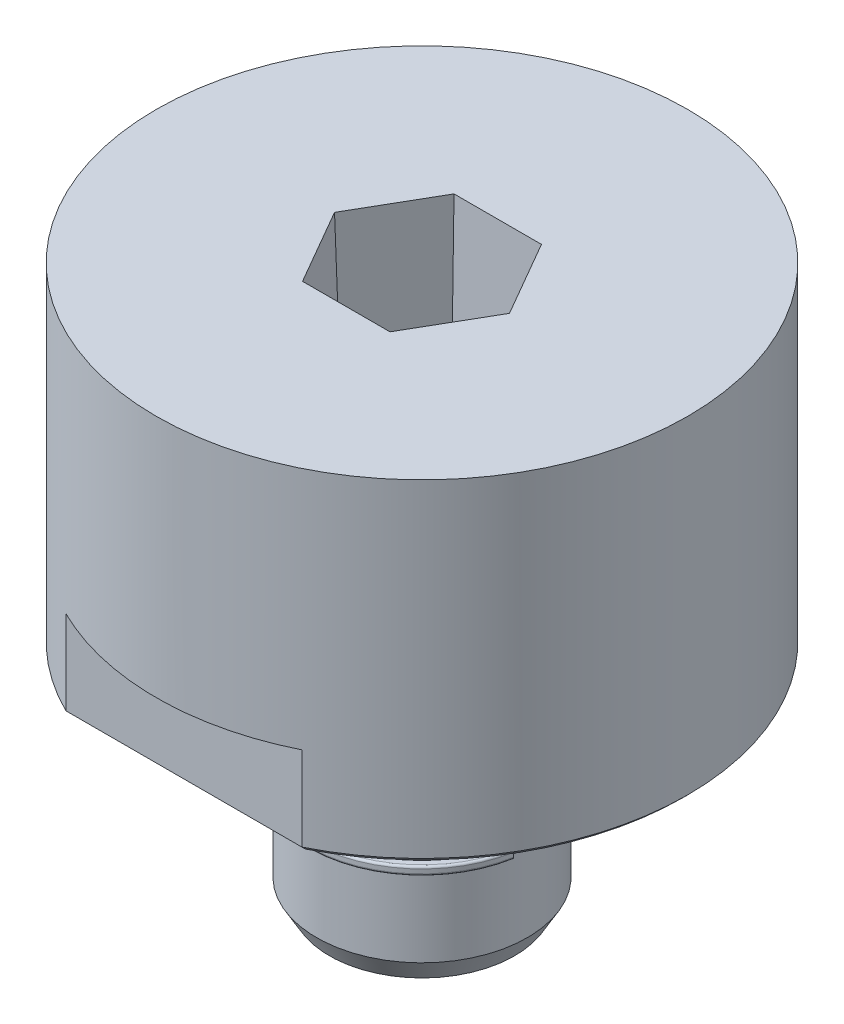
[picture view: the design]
ISO-10303-21;
HEADER;
FILE_DESCRIPTION(('STEP AP214'),'2;1');
FILE_NAME('part.step','',(''),(''),'','','');
FILE_SCHEMA(('AUTOMOTIVE_DESIGN { 1 0 10303 214 1 1 1 1 }'));
ENDSEC;
DATA;
#1=APPLICATION_CONTEXT('core data for automotive mechanical design processes');
#2=APPLICATION_PROTOCOL_DEFINITION('international standard','automotive_design',2000,#1);
#3=PRODUCT_CONTEXT('',#1,'mechanical');
#4=PRODUCT('Part','Part','',(#3));
#5=PRODUCT_RELATED_PRODUCT_CATEGORY('part','',(#4));
#6=PRODUCT_DEFINITION_FORMATION('','',#4);
#7=PRODUCT_DEFINITION_CONTEXT('part definition',#1,'design');
#8=PRODUCT_DEFINITION('design','',#6,#7);
#9=PRODUCT_DEFINITION_SHAPE('','',#8);
#10=(LENGTH_UNIT() NAMED_UNIT(*) SI_UNIT(.MILLI.,.METRE.));
#11=(NAMED_UNIT(*) PLANE_ANGLE_UNIT() SI_UNIT($,.RADIAN.));
#12=(NAMED_UNIT(*) SI_UNIT($,.STERADIAN.) SOLID_ANGLE_UNIT());
#13=UNCERTAINTY_MEASURE_WITH_UNIT(LENGTH_MEASURE(1.E-05),#10,'distance_accuracy_value','');
#14=(GEOMETRIC_REPRESENTATION_CONTEXT(3) GLOBAL_UNCERTAINTY_ASSIGNED_CONTEXT((#13)) GLOBAL_UNIT_ASSIGNED_CONTEXT((#10,
#11,#12)) REPRESENTATION_CONTEXT('',''));
#15=CARTESIAN_POINT('',(0.,0.,0.));
#16=DIRECTION('',(0.,0.,1.));
#17=DIRECTION('',(1.,0.,0.));
#18=AXIS2_PLACEMENT_3D('',#15,#16,#17);
#19=CARTESIAN_POINT('',(0.,3.5395,0.));
#20=DIRECTION('',(0.,-1.,0.));
#21=DIRECTION('',(1.,0.,0.));
#22=AXIS2_PLACEMENT_3D('',#19,#20,#21);
#23=CYLINDRICAL_SURFACE('',#22,4.4577);
#24=CARTESIAN_POINT('',(0.,4.71425,0.));
#25=DIRECTION('',(0.,-1.,0.));
#26=DIRECTION('',(0.,0.,-1.));
#27=AXIS2_PLACEMENT_3D('',#24,#25,#26);
#28=CIRCLE('',#27,4.4577);
#29=CARTESIAN_POINT('',(4.38997752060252,4.71425,0.774071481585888));
#30=VERTEX_POINT('',#29);
#31=CARTESIAN_POINT('',(4.38997752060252,4.71425,-0.774071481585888));
#32=VERTEX_POINT('',#31);
#33=EDGE_CURVE('E12',#30,#32,#28,.T.);
#34=ORIENTED_EDGE('',*,*,#33,.T.);
#35=DIRECTION('',(0.,1.,0.));
#36=VECTOR('',#35,1.);
#37=CARTESIAN_POINT('',(4.38997752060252,3.5395,-0.774071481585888));
#38=LINE('',#37,#36);
#39=CARTESIAN_POINT('',(4.38997752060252,4.90475,-0.774071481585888));
#40=VERTEX_POINT('',#39);
#41=EDGE_CURVE('E62',#32,#40,#38,.T.);
#42=ORIENTED_EDGE('',*,*,#41,.T.);
#43=CARTESIAN_POINT('',(0.,4.90475,0.));
#44=DIRECTION('',(0.,-1.,0.));
#45=DIRECTION('',(0.,0.,-1.));
#46=AXIS2_PLACEMENT_3D('',#43,#44,#45);
#47=CIRCLE('',#46,4.4577);
#48=CARTESIAN_POINT('',(4.38997752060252,4.90475,0.774071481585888));
#49=VERTEX_POINT('',#48);
#50=EDGE_CURVE('E137',#49,#40,#47,.T.);
#51=ORIENTED_EDGE('',*,*,#50,.F.);
#52=DIRECTION('',(0.,-1.,0.));
#53=VECTOR('',#52,1.);
#54=CARTESIAN_POINT('',(4.38997752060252,3.5395,0.774071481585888));
#55=LINE('',#54,#53);
#56=EDGE_CURVE('E202',#49,#30,#55,.T.);
#57=ORIENTED_EDGE('',*,*,#56,.T.);
#58=EDGE_LOOP('',(#34,#42,#51,#57));
#59=FACE_BOUND('',#58,.T.);
#60=ADVANCED_FACE('F54',(#59),#23,.F.);
#61=CARTESIAN_POINT('',(0.,5.1905,0.));
#62=DIRECTION('',(0.173648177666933,0.,-0.984807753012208));
#63=DIRECTION('',(-0.984807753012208,0.,-0.173648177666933));
#64=AXIS2_PLACEMENT_3D('',#61,#62,#63);
#65=PLANE('',#64);
#66=CARTESIAN_POINT('',(4.48378045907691,4.90475000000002,0.79061147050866));
#67=DIRECTION('',(-0.173648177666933,0.,0.984807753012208));
#68=DIRECTION('',(-0.984807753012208,0.,-0.173648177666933));
#69=AXIS2_PLACEMENT_3D('',#66,#67,#68);
#70=CIRCLE('',#69,0.09524999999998);
#71=CARTESIAN_POINT('',(4.48378045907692,5.,0.790611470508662));
#72=VERTEX_POINT('',#71);
#73=EDGE_CURVE('E198',#72,#49,#70,.T.);
#74=ORIENTED_EDGE('',*,*,#73,.F.);
#75=DIRECTION('',(-0.984807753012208,0.,-0.173648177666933));
#76=VECTOR('',#75,1.);
#77=CARTESIAN_POINT('',(4.84675844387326,5.,0.854614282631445));
#78=LINE('',#77,#76);
#79=CARTESIAN_POINT('',(4.92152750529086,5.,0.867798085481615));
#80=VERTEX_POINT('',#79);
#81=EDGE_CURVE('E131',#80,#72,#78,.T.);
#82=ORIENTED_EDGE('',*,*,#81,.F.);
#83=CARTESIAN_POINT('',(4.92152750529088,4.90475000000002,0.867798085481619));
#84=DIRECTION('',(-0.173648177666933,0.,0.984807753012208));
#85=DIRECTION('',(-0.984807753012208,0.,-0.173648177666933));
#86=AXIS2_PLACEMENT_3D('',#83,#84,#85);
#87=CIRCLE('',#86,0.0952499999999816);
#88=CARTESIAN_POINT('',(5.01533044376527,4.90475,0.884338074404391));
#89=VERTEX_POINT('',#88);
#90=EDGE_CURVE('E190',#89,#80,#87,.T.);
#91=ORIENTED_EDGE('',*,*,#90,.F.);
#92=DIRECTION('',(0.,1.,0.));
#93=VECTOR('',#92,1.);
#94=CARTESIAN_POINT('',(5.01533044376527,3.5395,0.884338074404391));
#95=LINE('',#94,#93);
#96=CARTESIAN_POINT('',(5.01533044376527,4.71425,0.884338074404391));
#97=VERTEX_POINT('',#96);
#98=EDGE_CURVE('E185',#97,#89,#95,.T.);
#99=ORIENTED_EDGE('',*,*,#98,.F.);
#100=CARTESIAN_POINT('',(4.92152750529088,4.71424999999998,0.867798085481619));
#101=DIRECTION('',(-0.173648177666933,0.,0.984807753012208));
#102=DIRECTION('',(-0.984807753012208,0.,-0.173648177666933));
#103=AXIS2_PLACEMENT_3D('',#100,#101,#102);
#104=CIRCLE('',#103,0.0952499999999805);
#105=CARTESIAN_POINT('',(4.92152750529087,4.619,0.867798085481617));
#106=VERTEX_POINT('',#105);
#107=EDGE_CURVE('E180',#106,#97,#104,.T.);
#108=ORIENTED_EDGE('',*,*,#107,.F.);
#109=DIRECTION('',(0.984807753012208,0.,0.173648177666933));
#110=VECTOR('',#109,1.);
#111=CARTESIAN_POINT('',(4.4156617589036,4.619,0.778600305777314));
#112=LINE('',#111,#110);
#113=CARTESIAN_POINT('',(4.48378045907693,4.619,0.790611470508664));
#114=VERTEX_POINT('',#113);
#115=EDGE_CURVE('E175',#114,#106,#112,.T.);
#116=ORIENTED_EDGE('',*,*,#115,.F.);
#117=CARTESIAN_POINT('',(4.48378045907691,4.71424999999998,0.79061147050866));
#118=DIRECTION('',(-0.173648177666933,0.,0.984807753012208));
#119=DIRECTION('',(-0.984807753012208,0.,-0.173648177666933));
#120=AXIS2_PLACEMENT_3D('',#117,#118,#119);
#121=CIRCLE('',#120,0.0952499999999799);
#122=EDGE_CURVE('E170',#30,#114,#121,.T.);
#123=ORIENTED_EDGE('',*,*,#122,.F.);
#124=ORIENTED_EDGE('',*,*,#56,.F.);
#125=EDGE_LOOP('',(#74,#82,#91,#99,#108,#116,#123,#124));
#126=FACE_BOUND('',#125,.T.);
#127=ADVANCED_FACE('F216',(#126),#65,.T.);
#128=CARTESIAN_POINT('',(0.,4.71424999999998,0.));
#129=DIRECTION('',(0.,-1.,0.));
#130=DIRECTION('',(1.,0.,0.));
#131=AXIS2_PLACEMENT_3D('',#128,#129,#130);
#132=TOROIDAL_SURFACE('',#131,4.55295,0.0952499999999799);
#133=CARTESIAN_POINT('',(0.,4.619,0.));
#134=DIRECTION('',(0.,-1.,0.));
#135=DIRECTION('',(0.,0.,-1.));
#136=AXIS2_PLACEMENT_3D('',#133,#134,#135);
#137=CIRCLE('',#136,4.55295);
#138=CARTESIAN_POINT('',(4.48378045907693,4.619,-0.790611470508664));
#139=VERTEX_POINT('',#138);
#140=EDGE_CURVE('E166',#114,#139,#137,.T.);
#141=ORIENTED_EDGE('',*,*,#140,.T.);
#142=CARTESIAN_POINT('',(4.48378045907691,4.71424999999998,-0.79061147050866));
#143=DIRECTION('',(-0.173648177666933,0.,-0.984807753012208));
#144=DIRECTION('',(0.984807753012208,0.,-0.173648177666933));
#145=AXIS2_PLACEMENT_3D('',#142,#143,#144);
#146=CIRCLE('',#145,0.0952499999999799);
#147=EDGE_CURVE('E162',#139,#32,#146,.T.);
#148=ORIENTED_EDGE('',*,*,#147,.T.);
#149=ORIENTED_EDGE('',*,*,#33,.F.);
#150=ORIENTED_EDGE('',*,*,#122,.T.);
#151=EDGE_LOOP('',(#141,#148,#149,#150));
#152=FACE_BOUND('',#151,.T.);
#153=ADVANCED_FACE('F219',(#152),#132,.T.);
#154=CARTESIAN_POINT('',(5.17291938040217,5.1905,-0.912125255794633));
#155=DIRECTION('',(0.173648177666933,0.,0.984807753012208));
#156=DIRECTION('',(0.984807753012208,0.,-0.173648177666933));
#157=AXIS2_PLACEMENT_3D('',#154,#155,#156);
#158=PLANE('',#157);
#159=ORIENTED_EDGE('',*,*,#147,.F.);
#160=DIRECTION('',(-0.984807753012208,0.,0.173648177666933));
#161=VECTOR('',#160,1.);
#162=CARTESIAN_POINT('',(4.4156617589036,4.619,-0.778600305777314));
#163=LINE('',#162,#161);
#164=CARTESIAN_POINT('',(4.92152750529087,4.619,-0.867798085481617));
#165=VERTEX_POINT('',#164);
#166=EDGE_CURVE('E157',#165,#139,#163,.T.);
#167=ORIENTED_EDGE('',*,*,#166,.F.);
#168=CARTESIAN_POINT('',(4.92152750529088,4.71424999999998,-0.867798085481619));
#169=DIRECTION('',(-0.173648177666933,0.,-0.984807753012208));
#170=DIRECTION('',(0.984807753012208,0.,-0.173648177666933));
#171=AXIS2_PLACEMENT_3D('',#168,#169,#170);
#172=CIRCLE('',#171,0.0952499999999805);
#173=CARTESIAN_POINT('',(5.01533044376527,4.71425,-0.884338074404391));
#174=VERTEX_POINT('',#173);
#175=EDGE_CURVE('E152',#174,#165,#172,.T.);
#176=ORIENTED_EDGE('',*,*,#175,.F.);
#177=DIRECTION('',(0.,-1.,0.));
#178=VECTOR('',#177,1.);
#179=CARTESIAN_POINT('',(5.01533044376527,3.5395,-0.884338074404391));
#180=LINE('',#179,#178);
#181=CARTESIAN_POINT('',(5.01533044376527,4.90475,-0.884338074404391));
#182=VERTEX_POINT('',#181);
#183=EDGE_CURVE('E147',#182,#174,#180,.T.);
#184=ORIENTED_EDGE('',*,*,#183,.F.);
#185=CARTESIAN_POINT('',(4.92152750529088,4.90475000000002,-0.867798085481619));
#186=DIRECTION('',(-0.173648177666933,0.,-0.984807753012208));
#187=DIRECTION('',(0.984807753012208,0.,-0.173648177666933));
#188=AXIS2_PLACEMENT_3D('',#185,#186,#187);
#189=CIRCLE('',#188,0.0952499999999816);
#190=CARTESIAN_POINT('',(4.92152750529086,5.,-0.867798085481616));
#191=VERTEX_POINT('',#190);
#192=EDGE_CURVE('E122',#191,#182,#189,.T.);
#193=ORIENTED_EDGE('',*,*,#192,.F.);
#194=DIRECTION('',(0.984807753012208,0.,-0.173648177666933));
#195=VECTOR('',#194,1.);
#196=CARTESIAN_POINT('',(4.84675844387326,5.,-0.854614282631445));
#197=LINE('',#196,#195);
#198=CARTESIAN_POINT('',(4.48378045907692,5.,-0.790611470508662));
#199=VERTEX_POINT('',#198);
#200=EDGE_CURVE('E114',#199,#191,#197,.T.);
#201=ORIENTED_EDGE('',*,*,#200,.F.);
#202=CARTESIAN_POINT('',(4.48378045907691,4.90475000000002,-0.79061147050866));
#203=DIRECTION('',(-0.173648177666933,0.,-0.984807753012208));
#204=DIRECTION('',(0.984807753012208,0.,-0.173648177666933));
#205=AXIS2_PLACEMENT_3D('',#202,#203,#204);
#206=CIRCLE('',#205,0.09524999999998);
#207=EDGE_CURVE('E119',#40,#199,#206,.T.);
#208=ORIENTED_EDGE('',*,*,#207,.F.);
#209=ORIENTED_EDGE('',*,*,#41,.F.);
#210=EDGE_LOOP('',(#159,#167,#176,#184,#193,#201,#208,#209));
#211=FACE_BOUND('',#210,.T.);
#212=ADVANCED_FACE('F117',(#211),#158,.T.);
#213=CARTESIAN_POINT('',(0.,4.90475000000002,0.));
#214=DIRECTION('',(0.,-1.,0.));
#215=DIRECTION('',(1.,0.,0.));
#216=AXIS2_PLACEMENT_3D('',#213,#214,#215);
#217=TOROIDAL_SURFACE('',#216,4.55295,0.09524999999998);
#218=ORIENTED_EDGE('',*,*,#50,.T.);
#219=ORIENTED_EDGE('',*,*,#207,.T.);
#220=CARTESIAN_POINT('',(0.,5.,0.));
#221=DIRECTION('',(0.,-1.,0.));
#222=DIRECTION('',(0.,0.,-1.));
#223=AXIS2_PLACEMENT_3D('',#220,#221,#222);
#224=CIRCLE('',#223,4.55295);
#225=EDGE_CURVE('E129',#72,#199,#224,.T.);
#226=ORIENTED_EDGE('',*,*,#225,.F.);
#227=ORIENTED_EDGE('',*,*,#73,.T.);
#228=EDGE_LOOP('',(#218,#219,#226,#227));
#229=FACE_BOUND('',#228,.T.);
#230=ADVANCED_FACE('F136',(#229),#217,.T.);
#231=CARTESIAN_POINT('',(4.99745,5.,0.));
#232=DIRECTION('',(0.,1.,0.));
#233=DIRECTION('',(0.,0.,1.));
#234=AXIS2_PLACEMENT_3D('',#231,#232,#233);
#235=PLANE('',#234);
#236=ORIENTED_EDGE('',*,*,#225,.T.);
#237=ORIENTED_EDGE('',*,*,#200,.T.);
#238=CARTESIAN_POINT('',(0.,5.,0.));
#239=DIRECTION('',(0.,-1.,0.));
#240=DIRECTION('',(0.,0.,-1.));
#241=AXIS2_PLACEMENT_3D('',#238,#239,#240);
#242=CIRCLE('',#241,4.99745);
#243=EDGE_CURVE('E134',#80,#191,#242,.T.);
#244=ORIENTED_EDGE('',*,*,#243,.F.);
#245=ORIENTED_EDGE('',*,*,#81,.T.);
#246=EDGE_LOOP('',(#236,#237,#244,#245));
#247=FACE_BOUND('',#246,.T.);
#248=ADVANCED_FACE('F130',(#247),#235,.T.);
#249=CARTESIAN_POINT('',(0.,4.90475000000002,0.));
#250=DIRECTION('',(0.,-1.,0.));
#251=DIRECTION('',(1.,0.,0.));
#252=AXIS2_PLACEMENT_3D('',#249,#250,#251);
#253=TOROIDAL_SURFACE('',#252,4.99745,0.0952499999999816);
#254=ORIENTED_EDGE('',*,*,#243,.T.);
#255=ORIENTED_EDGE('',*,*,#192,.T.);
#256=CARTESIAN_POINT('',(0.,4.90475,0.));
#257=DIRECTION('',(0.,-1.,0.));
#258=DIRECTION('',(0.,0.,-1.));
#259=AXIS2_PLACEMENT_3D('',#256,#257,#258);
#260=CIRCLE('',#259,5.0927);
#261=EDGE_CURVE('E232',#89,#182,#260,.T.);
#262=ORIENTED_EDGE('',*,*,#261,.F.);
#263=ORIENTED_EDGE('',*,*,#90,.T.);
#264=EDGE_LOOP('',(#254,#255,#262,#263));
#265=FACE_BOUND('',#264,.T.);
#266=ADVANCED_FACE('F246',(#265),#253,.T.);
#267=CARTESIAN_POINT('',(0.,3.5395,0.));
#268=DIRECTION('',(0.,-1.,0.));
#269=DIRECTION('',(1.,0.,0.));
#270=AXIS2_PLACEMENT_3D('',#267,#268,#269);
#271=CYLINDRICAL_SURFACE('',#270,5.0927);
#272=ORIENTED_EDGE('',*,*,#261,.T.);
#273=ORIENTED_EDGE('',*,*,#183,.T.);
#274=CARTESIAN_POINT('',(0.,4.71425,0.));
#275=DIRECTION('',(0.,-1.,0.));
#276=DIRECTION('',(0.,0.,-1.));
#277=AXIS2_PLACEMENT_3D('',#274,#275,#276);
#278=CIRCLE('',#277,5.0927);
#279=EDGE_CURVE('E226',#97,#174,#278,.T.);
#280=ORIENTED_EDGE('',*,*,#279,.F.);
#281=ORIENTED_EDGE('',*,*,#98,.T.);
#282=EDGE_LOOP('',(#272,#273,#280,#281));
#283=FACE_BOUND('',#282,.T.);
#284=ADVANCED_FACE('F248',(#283),#271,.T.);
#285=CARTESIAN_POINT('',(0.,4.71424999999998,0.));
#286=DIRECTION('',(0.,-1.,0.));
#287=DIRECTION('',(1.,0.,0.));
#288=AXIS2_PLACEMENT_3D('',#285,#286,#287);
#289=TOROIDAL_SURFACE('',#288,4.99745,0.0952499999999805);
#290=ORIENTED_EDGE('',*,*,#279,.T.);
#291=ORIENTED_EDGE('',*,*,#175,.T.);
#292=CARTESIAN_POINT('',(0.,4.619,0.));
#293=DIRECTION('',(0.,-1.,0.));
#294=DIRECTION('',(0.,0.,-1.));
#295=AXIS2_PLACEMENT_3D('',#292,#293,#294);
#296=CIRCLE('',#295,4.99745);
#297=EDGE_CURVE('E223',#106,#165,#296,.T.);
#298=ORIENTED_EDGE('',*,*,#297,.F.);
#299=ORIENTED_EDGE('',*,*,#107,.T.);
#300=EDGE_LOOP('',(#290,#291,#298,#299));
#301=FACE_BOUND('',#300,.T.);
#302=ADVANCED_FACE('F229',(#301),#289,.T.);
#303=CARTESIAN_POINT('',(4.55295,4.619,0.));
#304=DIRECTION('',(0.,-1.,0.));
#305=DIRECTION('',(0.,0.,-1.));
#306=AXIS2_PLACEMENT_3D('',#303,#304,#305);
#307=PLANE('',#306);
#308=ORIENTED_EDGE('',*,*,#297,.T.);
#309=ORIENTED_EDGE('',*,*,#166,.T.);
#310=ORIENTED_EDGE('',*,*,#140,.F.);
#311=ORIENTED_EDGE('',*,*,#115,.T.);
#312=EDGE_LOOP('',(#308,#309,#310,#311));
#313=FACE_BOUND('',#312,.T.);
#314=ADVANCED_FACE('F224',(#313),#307,.T.);
#315=CLOSED_SHELL('',(#60,#127,#153,#212,#230,#248,#266,#284,#302,#314));
#316=MANIFOLD_SOLID_BREP('B2',#315);
#317=CARTESIAN_POINT('',(4.18264973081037,0.,0.));
#318=DIRECTION('',(0.,-1.,0.));
#319=DIRECTION('',(0.,0.,-1.));
#320=AXIS2_PLACEMENT_3D('',#317,#318,#319);
#321=PLANE('',#320);
#322=CARTESIAN_POINT('',(0.,0.,0.));
#323=DIRECTION('',(0.,-1.,0.));
#324=DIRECTION('',(0.,0.,-1.));
#325=AXIS2_PLACEMENT_3D('',#322,#323,#324);
#326=CIRCLE('',#325,3.00000000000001);
#327=CARTESIAN_POINT('',(0.,0.,-3.00000000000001));
#328=VERTEX_POINT('',#327);
#329=EDGE_CURVE('E360',#328,#328,#326,.F.);
#330=ORIENTED_EDGE('',*,*,#329,.T.);
#331=EDGE_LOOP('',(#330));
#332=FACE_BOUND('',#331,.T.);
#333=CARTESIAN_POINT('',(0.,0.,0.));
#334=DIRECTION('',(0.,-1.,0.));
#335=DIRECTION('',(0.,0.,-1.));
#336=AXIS2_PLACEMENT_3D('',#333,#334,#335);
#337=CIRCLE('',#336,4.18264973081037);
#338=CARTESIAN_POINT('',(0.,0.,-4.18264973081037));
#339=VERTEX_POINT('',#338);
#340=EDGE_CURVE('E554',#339,#339,#337,.T.);
#341=ORIENTED_EDGE('',*,*,#340,.T.);
#342=EDGE_LOOP('',(#341));
#343=FACE_BOUND('',#342,.T.);
#344=ADVANCED_FACE('F350',(#332,#343),#321,.T.);
#345=CARTESIAN_POINT('',(0.,25.,0.));
#346=DIRECTION('',(0.,1.,0.));
#347=DIRECTION('',(0.,0.,1.));
#348=AXIS2_PLACEMENT_3D('',#345,#346,#347);
#349=PLANE('',#348);
#350=DIRECTION('',(0.5,0.,0.866025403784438));
#351=VECTOR('',#350,1.);
#352=CARTESIAN_POINT('',(2.96098349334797,25.,-1.70952461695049));
#353=LINE('',#352,#351);
#354=CARTESIAN_POINT('',(3.94797799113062,25.,0.));
#355=VERTEX_POINT('',#354);
#356=CARTESIAN_POINT('',(1.97398899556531,25.,-3.41904923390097));
#357=VERTEX_POINT('',#356);
#358=EDGE_CURVE('E517',#355,#357,#353,.F.);
#359=ORIENTED_EDGE('',*,*,#358,.F.);
#360=DIRECTION('',(-0.5,0.,0.866025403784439));
#361=VECTOR('',#360,1.);
#362=CARTESIAN_POINT('',(2.96098349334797,25.,1.70952461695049));
#363=LINE('',#362,#361);
#364=CARTESIAN_POINT('',(1.97398899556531,25.,3.41904923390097));
#365=VERTEX_POINT('',#364);
#366=EDGE_CURVE('E427',#365,#355,#363,.F.);
#367=ORIENTED_EDGE('',*,*,#366,.F.);
#368=DIRECTION('',(-1.,0.,0.));
#369=VECTOR('',#368,1.);
#370=CARTESIAN_POINT('',(0.,25.,3.41904923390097));
#371=LINE('',#370,#369);
#372=CARTESIAN_POINT('',(-1.97398899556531,25.,3.41904923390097));
#373=VERTEX_POINT('',#372);
#374=EDGE_CURVE('E405',#373,#365,#371,.F.);
#375=ORIENTED_EDGE('',*,*,#374,.F.);
#376=DIRECTION('',(-0.5,0.,-0.866025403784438));
#377=VECTOR('',#376,1.);
#378=CARTESIAN_POINT('',(-2.96098349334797,25.,1.70952461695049));
#379=LINE('',#378,#377);
#380=CARTESIAN_POINT('',(-3.94797799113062,25.,0.));
#381=VERTEX_POINT('',#380);
#382=EDGE_CURVE('E416',#381,#373,#379,.F.);
#383=ORIENTED_EDGE('',*,*,#382,.F.);
#384=DIRECTION('',(0.5,0.,-0.866025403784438));
#385=VECTOR('',#384,1.);
#386=CARTESIAN_POINT('',(-2.96098349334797,25.,-1.70952461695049));
#387=LINE('',#386,#385);
#388=CARTESIAN_POINT('',(-1.97398899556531,25.,-3.41904923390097));
#389=VERTEX_POINT('',#388);
#390=EDGE_CURVE('E422',#389,#381,#387,.F.);
#391=ORIENTED_EDGE('',*,*,#390,.F.);
#392=DIRECTION('',(1.,0.,0.));
#393=VECTOR('',#392,1.);
#394=CARTESIAN_POINT('',(0.,25.,-3.41904923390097));
#395=LINE('',#394,#393);
#396=EDGE_CURVE('E515',#357,#389,#395,.F.);
#397=ORIENTED_EDGE('',*,*,#396,.F.);
#398=EDGE_LOOP('',(#359,#367,#375,#383,#391,#397));
#399=FACE_BOUND('',#398,.T.);
#400=CARTESIAN_POINT('',(0.,25.,0.));
#401=DIRECTION('',(0.,-1.,0.));
#402=DIRECTION('',(0.,0.,-1.));
#403=AXIS2_PLACEMENT_3D('',#400,#401,#402);
#404=CIRCLE('',#403,11.9975);
#405=CARTESIAN_POINT('',(0.,25.,-11.9975));
#406=VERTEX_POINT('',#405);
#407=EDGE_CURVE('E588',#406,#406,#404,.T.);
#408=ORIENTED_EDGE('',*,*,#407,.F.);
#409=EDGE_LOOP('',(#408));
#410=FACE_BOUND('',#409,.T.);
#411=ADVANCED_FACE('F425',(#399,#410),#349,.T.);
#412=CARTESIAN_POINT('',(0.,0.,0.));
#413=DIRECTION('',(0.,-1.,0.));
#414=DIRECTION('',(0.,0.,-1.));
#415=AXIS2_PLACEMENT_3D('',#412,#413,#414);
#416=CYLINDRICAL_SURFACE('',#415,11.9975);
#417=DIRECTION('',(0.,-1.,0.));
#418=VECTOR('',#417,1.);
#419=CARTESIAN_POINT('',(5.32705418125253,14.,10.75));
#420=LINE('',#419,#418);
#421=CARTESIAN_POINT('',(5.32705418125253,14.,10.75));
#422=VERTEX_POINT('',#421);
#423=CARTESIAN_POINT('',(5.32705418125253,10.2,10.75));
#424=VERTEX_POINT('',#423);
#425=EDGE_CURVE('E552',#422,#424,#420,.T.);
#426=ORIENTED_EDGE('',*,*,#425,.T.);
#427=CARTESIAN_POINT('',(0.,10.2,0.));
#428=DIRECTION('',(0.,-1.,0.));
#429=DIRECTION('',(0.,0.,-1.));
#430=AXIS2_PLACEMENT_3D('',#427,#428,#429);
#431=CIRCLE('',#430,11.9975);
#432=CARTESIAN_POINT('',(5.32705418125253,10.2,-10.75));
#433=VERTEX_POINT('',#432);
#434=EDGE_CURVE('E436',#424,#433,#431,.F.);
#435=ORIENTED_EDGE('',*,*,#434,.T.);
#436=DIRECTION('',(0.,-1.,0.));
#437=VECTOR('',#436,1.);
#438=CARTESIAN_POINT('',(5.32705418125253,14.,-10.75));
#439=LINE('',#438,#437);
#440=CARTESIAN_POINT('',(5.32705418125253,14.,-10.75));
#441=VERTEX_POINT('',#440);
#442=EDGE_CURVE('E556',#441,#433,#439,.T.);
#443=ORIENTED_EDGE('',*,*,#442,.F.);
#444=CARTESIAN_POINT('',(0.,14.,0.));
#445=DIRECTION('',(0.,-1.,0.));
#446=DIRECTION('',(0.,0.,-1.));
#447=AXIS2_PLACEMENT_3D('',#444,#445,#446);
#448=CIRCLE('',#447,11.9975);
#449=CARTESIAN_POINT('',(-5.32705418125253,14.,-10.75));
#450=VERTEX_POINT('',#449);
#451=EDGE_CURVE('E548',#450,#441,#448,.T.);
#452=ORIENTED_EDGE('',*,*,#451,.F.);
#453=DIRECTION('',(0.,-1.,0.));
#454=VECTOR('',#453,1.);
#455=CARTESIAN_POINT('',(-5.32705418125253,14.,-10.75));
#456=LINE('',#455,#454);
#457=CARTESIAN_POINT('',(-5.32705418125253,10.2,-10.75));
#458=VERTEX_POINT('',#457);
#459=EDGE_CURVE('E508',#450,#458,#456,.T.);
#460=ORIENTED_EDGE('',*,*,#459,.T.);
#461=CARTESIAN_POINT('',(0.,10.2,0.));
#462=DIRECTION('',(0.,-1.,0.));
#463=DIRECTION('',(0.,0.,-1.));
#464=AXIS2_PLACEMENT_3D('',#461,#462,#463);
#465=CIRCLE('',#464,11.9975);
#466=CARTESIAN_POINT('',(-5.32705418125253,10.2,10.75));
#467=VERTEX_POINT('',#466);
#468=EDGE_CURVE('E368',#458,#467,#465,.F.);
#469=ORIENTED_EDGE('',*,*,#468,.T.);
#470=DIRECTION('',(0.,-1.,0.));
#471=VECTOR('',#470,1.);
#472=CARTESIAN_POINT('',(-5.32705418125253,14.,10.75));
#473=LINE('',#472,#471);
#474=CARTESIAN_POINT('',(-5.32705418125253,14.,10.75));
#475=VERTEX_POINT('',#474);
#476=EDGE_CURVE('E551',#475,#467,#473,.T.);
#477=ORIENTED_EDGE('',*,*,#476,.F.);
#478=CARTESIAN_POINT('',(0.,14.,0.));
#479=DIRECTION('',(0.,-1.,0.));
#480=DIRECTION('',(0.,0.,-1.));
#481=AXIS2_PLACEMENT_3D('',#478,#479,#480);
#482=CIRCLE('',#481,11.9975);
#483=EDGE_CURVE('E544',#422,#475,#482,.T.);
#484=ORIENTED_EDGE('',*,*,#483,.F.);
#485=EDGE_LOOP('',(#426,#435,#443,#452,#460,#469,#477,#484));
#486=FACE_BOUND('',#485,.T.);
#487=ORIENTED_EDGE('',*,*,#407,.T.);
#488=EDGE_LOOP('',(#487));
#489=FACE_BOUND('',#488,.T.);
#490=ADVANCED_FACE('F632',(#486,#489),#416,.T.);
#491=CARTESIAN_POINT('',(11.9975,10.,0.));
#492=DIRECTION('',(0.,-1.,0.));
#493=DIRECTION('',(0.,0.,-1.));
#494=AXIS2_PLACEMENT_3D('',#491,#492,#493);
#495=PLANE('',#494);
#496=CARTESIAN_POINT('',(0.,10.,0.));
#497=DIRECTION('',(0.,-1.,0.));
#498=DIRECTION('',(0.,0.,-1.));
#499=AXIS2_PLACEMENT_3D('',#496,#497,#498);
#500=CIRCLE('',#499,11.7975);
#501=CARTESIAN_POINT('',(-5.28001006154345,10.,10.55));
#502=VERTEX_POINT('',#501);
#503=CARTESIAN_POINT('',(-5.28001006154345,10.,-10.55));
#504=VERTEX_POINT('',#503);
#505=EDGE_CURVE('E594',#502,#504,#500,.T.);
#506=ORIENTED_EDGE('',*,*,#505,.T.);
#507=DIRECTION('',(1.,0.,0.));
#508=VECTOR('',#507,1.);
#509=CARTESIAN_POINT('',(5.32705418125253,10.,-10.55));
#510=LINE('',#509,#508);
#511=CARTESIAN_POINT('',(5.28001006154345,10.,-10.55));
#512=VERTEX_POINT('',#511);
#513=EDGE_CURVE('E603',#504,#512,#510,.T.);
#514=ORIENTED_EDGE('',*,*,#513,.T.);
#515=CARTESIAN_POINT('',(0.,10.,0.));
#516=DIRECTION('',(0.,-1.,0.));
#517=DIRECTION('',(0.,0.,-1.));
#518=AXIS2_PLACEMENT_3D('',#515,#516,#517);
#519=CIRCLE('',#518,11.7975);
#520=CARTESIAN_POINT('',(5.28001006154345,10.,10.55));
#521=VERTEX_POINT('',#520);
#522=EDGE_CURVE('E600',#512,#521,#519,.T.);
#523=ORIENTED_EDGE('',*,*,#522,.T.);
#524=DIRECTION('',(-1.,0.,0.));
#525=VECTOR('',#524,1.);
#526=CARTESIAN_POINT('',(-5.32705418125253,10.,10.55));
#527=LINE('',#526,#525);
#528=EDGE_CURVE('E597',#521,#502,#527,.T.);
#529=ORIENTED_EDGE('',*,*,#528,.T.);
#530=EDGE_LOOP('',(#506,#514,#523,#529));
#531=FACE_BOUND('',#530,.T.);
#532=CARTESIAN_POINT('',(6.50538238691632,10.,-6.50538238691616));
#533=DIRECTION('',(0.,-1.,0.));
#534=DIRECTION('',(-0.707106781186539,0.,-0.707106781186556));
#535=AXIS2_PLACEMENT_3D('',#532,#533,#534);
#536=CIRCLE('',#535,0.916515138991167);
#537=CARTESIAN_POINT('',(5.85730831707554,10.,-7.15345645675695));
#538=VERTEX_POINT('',#537);
#539=EDGE_CURVE('E496',#538,#538,#536,.T.);
#540=ORIENTED_EDGE('',*,*,#539,.F.);
#541=EDGE_LOOP('',(#540));
#542=FACE_BOUND('',#541,.T.);
#543=CARTESIAN_POINT('',(0.,10.,-9.2));
#544=DIRECTION('',(0.,-1.,0.));
#545=DIRECTION('',(-1.,0.,0.));
#546=AXIS2_PLACEMENT_3D('',#543,#544,#545);
#547=CIRCLE('',#546,0.916515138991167);
#548=CARTESIAN_POINT('',(-0.916515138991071,10.,-9.20000000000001));
#549=VERTEX_POINT('',#548);
#550=EDGE_CURVE('E1076',#549,#549,#547,.T.);
#551=ORIENTED_EDGE('',*,*,#550,.F.);
#552=EDGE_LOOP('',(#551));
#553=FACE_BOUND('',#552,.T.);
#554=CARTESIAN_POINT('',(-6.50538238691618,10.,-6.50538238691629));
#555=DIRECTION('',(0.,-1.,0.));
#556=DIRECTION('',(-0.707106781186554,0.,0.707106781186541));
#557=AXIS2_PLACEMENT_3D('',#554,#555,#556);
#558=CIRCLE('',#557,0.916515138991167);
#559=CARTESIAN_POINT('',(-7.15345645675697,10.,-5.85730831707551));
#560=VERTEX_POINT('',#559);
#561=EDGE_CURVE('E1073',#560,#560,#558,.T.);
#562=ORIENTED_EDGE('',*,*,#561,.F.);
#563=EDGE_LOOP('',(#562));
#564=FACE_BOUND('',#563,.T.);
#565=CARTESIAN_POINT('',(-9.2,10.,0.));
#566=DIRECTION('',(0.,-1.,0.));
#567=DIRECTION('',(0.,0.,1.));
#568=AXIS2_PLACEMENT_3D('',#565,#566,#567);
#569=CIRCLE('',#568,0.916515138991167);
#570=CARTESIAN_POINT('',(-9.2,10.,0.916515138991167));
#571=VERTEX_POINT('',#570);
#572=EDGE_CURVE('E1068',#571,#571,#569,.T.);
#573=ORIENTED_EDGE('',*,*,#572,.F.);
#574=EDGE_LOOP('',(#573));
#575=FACE_BOUND('',#574,.T.);
#576=CARTESIAN_POINT('',(-6.50538238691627,10.,6.5053823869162));
#577=DIRECTION('',(0.,-1.,0.));
#578=DIRECTION('',(0.707106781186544,0.,0.707106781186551));
#579=AXIS2_PLACEMENT_3D('',#576,#577,#578);
#580=CIRCLE('',#579,0.916515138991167);
#581=CARTESIAN_POINT('',(-5.85730831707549,10.,7.15345645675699));
#582=VERTEX_POINT('',#581);
#583=EDGE_CURVE('E1066',#582,#582,#580,.T.);
#584=ORIENTED_EDGE('',*,*,#583,.F.);
#585=EDGE_LOOP('',(#584));
#586=FACE_BOUND('',#585,.T.);
#587=CARTESIAN_POINT('',(0.,10.,9.2));
#588=DIRECTION('',(0.,-1.,0.));
#589=DIRECTION('',(1.,0.,0.));
#590=AXIS2_PLACEMENT_3D('',#587,#588,#589);
#591=CIRCLE('',#590,0.916515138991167);
#592=CARTESIAN_POINT('',(0.916515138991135,10.,9.2));
#593=VERTEX_POINT('',#592);
#594=EDGE_CURVE('E527',#593,#593,#591,.T.);
#595=ORIENTED_EDGE('',*,*,#594,.F.);
#596=EDGE_LOOP('',(#595));
#597=FACE_BOUND('',#596,.T.);
#598=CARTESIAN_POINT('',(6.50538238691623,10.,6.50538238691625));
#599=DIRECTION('',(0.,-1.,0.));
#600=DIRECTION('',(0.707106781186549,0.,-0.707106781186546));
#601=AXIS2_PLACEMENT_3D('',#598,#599,#600);
#602=CIRCLE('',#601,0.916515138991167);
#603=CARTESIAN_POINT('',(7.15345645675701,10.,5.85730831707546));
#604=VERTEX_POINT('',#603);
#605=EDGE_CURVE('E522',#604,#604,#602,.T.);
#606=ORIENTED_EDGE('',*,*,#605,.F.);
#607=EDGE_LOOP('',(#606));
#608=FACE_BOUND('',#607,.T.);
#609=CARTESIAN_POINT('',(9.2,10.,0.));
#610=DIRECTION('',(0.,-1.,0.));
#611=DIRECTION('',(0.,0.,-1.));
#612=AXIS2_PLACEMENT_3D('',#609,#610,#611);
#613=CIRCLE('',#612,0.916515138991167);
#614=CARTESIAN_POINT('',(9.2,10.,-0.916515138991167));
#615=VERTEX_POINT('',#614);
#616=EDGE_CURVE('E518',#615,#615,#613,.T.);
#617=ORIENTED_EDGE('',*,*,#616,.F.);
#618=EDGE_LOOP('',(#617));
#619=FACE_BOUND('',#618,.T.);
#620=CARTESIAN_POINT('',(0.,10.,0.));
#621=DIRECTION('',(0.,-1.,0.));
#622=DIRECTION('',(0.,0.,-1.));
#623=AXIS2_PLACEMENT_3D('',#620,#621,#622);
#624=CIRCLE('',#623,5.56);
#625=CARTESIAN_POINT('',(0.,10.,-5.56));
#626=VERTEX_POINT('',#625);
#627=EDGE_CURVE('E585',#626,#626,#624,.T.);
#628=ORIENTED_EDGE('',*,*,#627,.F.);
#629=EDGE_LOOP('',(#628));
#630=FACE_BOUND('',#629,.T.);
#631=ADVANCED_FACE('F607',(#531,#542,#553,#564,#575,#586,#597,#608,#619,#630),#495,.T.);
#632=CARTESIAN_POINT('',(0.,9.2,0.));
#633=DIRECTION('',(0.,-1.,0.));
#634=DIRECTION('',(0.,0.,-1.));
#635=AXIS2_PLACEMENT_3D('',#632,#633,#634);
#636=TOROIDAL_SURFACE('',#635,5.56,0.8);
#637=ORIENTED_EDGE('',*,*,#627,.T.);
#638=EDGE_LOOP('',(#637));
#639=FACE_BOUND('',#638,.T.);
#640=CARTESIAN_POINT('',(0.,9.2,0.));
#641=DIRECTION('',(0.,-1.,0.));
#642=DIRECTION('',(0.,0.,-1.));
#643=AXIS2_PLACEMENT_3D('',#640,#641,#642);
#644=CIRCLE('',#643,4.76);
#645=CARTESIAN_POINT('',(0.,9.2,-4.76));
#646=VERTEX_POINT('',#645);
#647=EDGE_CURVE('E582',#646,#646,#644,.T.);
#648=ORIENTED_EDGE('',*,*,#647,.F.);
#649=EDGE_LOOP('',(#648));
#650=FACE_BOUND('',#649,.T.);
#651=ADVANCED_FACE('F676',(#639,#650),#636,.F.);
#652=CARTESIAN_POINT('',(0.,0.,0.));
#653=DIRECTION('',(0.,-1.,0.));
#654=DIRECTION('',(0.,0.,-1.));
#655=AXIS2_PLACEMENT_3D('',#652,#653,#654);
#656=CYLINDRICAL_SURFACE('',#655,4.76);
#657=ORIENTED_EDGE('',*,*,#647,.T.);
#658=EDGE_LOOP('',(#657));
#659=FACE_BOUND('',#658,.T.);
#660=CARTESIAN_POINT('',(0.,5.,0.));
#661=DIRECTION('',(0.,-1.,0.));
#662=DIRECTION('',(0.,0.,-1.));
#663=AXIS2_PLACEMENT_3D('',#660,#661,#662);
#664=CIRCLE('',#663,4.76);
#665=CARTESIAN_POINT('',(0.,5.,-4.76));
#666=VERTEX_POINT('',#665);
#667=EDGE_CURVE('E579',#666,#666,#664,.T.);
#668=ORIENTED_EDGE('',*,*,#667,.F.);
#669=EDGE_LOOP('',(#668));
#670=FACE_BOUND('',#669,.T.);
#671=ADVANCED_FACE('F679',(#659,#670),#656,.T.);
#672=CARTESIAN_POINT('',(4.76,5.,0.));
#673=DIRECTION('',(0.,-1.,0.));
#674=DIRECTION('',(0.,0.,-1.));
#675=AXIS2_PLACEMENT_3D('',#672,#673,#674);
#676=PLANE('',#675);
#677=ORIENTED_EDGE('',*,*,#667,.T.);
#678=EDGE_LOOP('',(#677));
#679=FACE_BOUND('',#678,.T.);
#680=CARTESIAN_POINT('',(0.,5.,0.));
#681=DIRECTION('',(0.,-1.,0.));
#682=DIRECTION('',(0.,0.,-1.));
#683=AXIS2_PLACEMENT_3D('',#680,#681,#682);
#684=CIRCLE('',#683,4.455);
#685=CARTESIAN_POINT('',(0.,5.,-4.455));
#686=VERTEX_POINT('',#685);
#687=EDGE_CURVE('E576',#686,#686,#684,.T.);
#688=ORIENTED_EDGE('',*,*,#687,.F.);
#689=EDGE_LOOP('',(#688));
#690=FACE_BOUND('',#689,.T.);
#691=ADVANCED_FACE('F683',(#679,#690),#676,.T.);
#692=CARTESIAN_POINT('',(0.,0.,0.));
#693=DIRECTION('',(0.,-1.,0.));
#694=DIRECTION('',(0.,0.,-1.));
#695=AXIS2_PLACEMENT_3D('',#692,#693,#694);
#696=CYLINDRICAL_SURFACE('',#695,4.455);
#697=ORIENTED_EDGE('',*,*,#687,.T.);
#698=EDGE_LOOP('',(#697));
#699=FACE_BOUND('',#698,.T.);
#700=CARTESIAN_POINT('',(0.,4.54,0.));
#701=DIRECTION('',(0.,-1.,0.));
#702=DIRECTION('',(0.,0.,-1.));
#703=AXIS2_PLACEMENT_3D('',#700,#701,#702);
#704=CIRCLE('',#703,4.455);
#705=CARTESIAN_POINT('',(0.,4.54,-4.455));
#706=VERTEX_POINT('',#705);
#707=EDGE_CURVE('E573',#706,#706,#704,.T.);
#708=ORIENTED_EDGE('',*,*,#707,.F.);
#709=EDGE_LOOP('',(#708));
#710=FACE_BOUND('',#709,.T.);
#711=ADVANCED_FACE('F687',(#699,#710),#696,.T.);
#712=CARTESIAN_POINT('',(4.455,4.54,0.));
#713=DIRECTION('',(0.,1.,0.));
#714=DIRECTION('',(0.,0.,1.));
#715=AXIS2_PLACEMENT_3D('',#712,#713,#714);
#716=PLANE('',#715);
#717=ORIENTED_EDGE('',*,*,#707,.T.);
#718=EDGE_LOOP('',(#717));
#719=FACE_BOUND('',#718,.T.);
#720=CARTESIAN_POINT('',(0.,4.54,0.));
#721=DIRECTION('',(0.,-1.,0.));
#722=DIRECTION('',(0.,0.,-1.));
#723=AXIS2_PLACEMENT_3D('',#720,#721,#722);
#724=CIRCLE('',#723,4.76);
#725=CARTESIAN_POINT('',(0.,4.54,-4.76));
#726=VERTEX_POINT('',#725);
#727=EDGE_CURVE('E570',#726,#726,#724,.T.);
#728=ORIENTED_EDGE('',*,*,#727,.F.);
#729=EDGE_LOOP('',(#728));
#730=FACE_BOUND('',#729,.T.);
#731=ADVANCED_FACE('F691',(#719,#730),#716,.T.);
#732=CARTESIAN_POINT('',(0.,0.,0.));
#733=DIRECTION('',(0.,-1.,0.));
#734=DIRECTION('',(0.,0.,-1.));
#735=AXIS2_PLACEMENT_3D('',#732,#733,#734);
#736=CYLINDRICAL_SURFACE('',#735,4.76);
#737=ORIENTED_EDGE('',*,*,#727,.T.);
#738=EDGE_LOOP('',(#737));
#739=FACE_BOUND('',#738,.T.);
#740=CARTESIAN_POINT('',(0.,1.,0.));
#741=DIRECTION('',(0.,-1.,0.));
#742=DIRECTION('',(0.,0.,-1.));
#743=AXIS2_PLACEMENT_3D('',#740,#741,#742);
#744=CIRCLE('',#743,4.76);
#745=CARTESIAN_POINT('',(0.,1.,-4.76));
#746=VERTEX_POINT('',#745);
#747=EDGE_CURVE('E567',#746,#746,#744,.T.);
#748=ORIENTED_EDGE('',*,*,#747,.F.);
#749=EDGE_LOOP('',(#748));
#750=FACE_BOUND('',#749,.T.);
#751=ADVANCED_FACE('F695',(#739,#750),#736,.T.);
#752=CARTESIAN_POINT('',(0.,0.,0.));
#753=DIRECTION('',(0.,1.,0.));
#754=DIRECTION('',(0.,0.,1.));
#755=AXIS2_PLACEMENT_3D('',#752,#753,#754);
#756=CONICAL_SURFACE('',#755,4.18264973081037,0.5235987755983);
#757=ORIENTED_EDGE('',*,*,#747,.T.);
#758=EDGE_LOOP('',(#757));
#759=FACE_BOUND('',#758,.T.);
#760=ORIENTED_EDGE('',*,*,#340,.F.);
#761=EDGE_LOOP('',(#760));
#762=FACE_BOUND('',#761,.T.);
#763=ADVANCED_FACE('F699',(#759,#762),#756,.T.);
#764=CARTESIAN_POINT('',(-5.32705418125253,14.,-10.75));
#765=DIRECTION('',(0.,0.,1.));
#766=DIRECTION('',(1.,0.,0.));
#767=AXIS2_PLACEMENT_3D('',#764,#765,#766);
#768=PLANE('',#767);
#769=ORIENTED_EDGE('',*,*,#442,.T.);
#770=DIRECTION('',(-1.,0.,0.));
#771=VECTOR('',#770,1.);
#772=CARTESIAN_POINT('',(-5.32705418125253,10.2,-10.75));
#773=LINE('',#772,#771);
#774=EDGE_CURVE('E591',#433,#458,#773,.T.);
#775=ORIENTED_EDGE('',*,*,#774,.T.);
#776=ORIENTED_EDGE('',*,*,#459,.F.);
#777=DIRECTION('',(-1.,0.,0.));
#778=VECTOR('',#777,1.);
#779=CARTESIAN_POINT('',(-5.32705418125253,14.,-10.75));
#780=LINE('',#779,#778);
#781=EDGE_CURVE('E559',#441,#450,#780,.T.);
#782=ORIENTED_EDGE('',*,*,#781,.F.);
#783=EDGE_LOOP('',(#769,#775,#776,#782));
#784=FACE_BOUND('',#783,.T.);
#785=ADVANCED_FACE('F627',(#784),#768,.F.);
#786=CARTESIAN_POINT('',(0.,14.,0.));
#787=DIRECTION('',(0.,-1.,0.));
#788=DIRECTION('',(0.,0.,-1.));
#789=AXIS2_PLACEMENT_3D('',#786,#787,#788);
#790=PLANE('',#789);
#791=ORIENTED_EDGE('',*,*,#451,.T.);
#792=ORIENTED_EDGE('',*,*,#781,.T.);
#793=EDGE_LOOP('',(#791,#792));
#794=FACE_BOUND('',#793,.T.);
#795=ADVANCED_FACE('F638',(#794),#790,.T.);
#796=CARTESIAN_POINT('',(-5.32705418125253,14.,10.75));
#797=DIRECTION('',(0.,0.,-1.));
#798=DIRECTION('',(-1.,0.,0.));
#799=AXIS2_PLACEMENT_3D('',#796,#797,#798);
#800=PLANE('',#799);
#801=ORIENTED_EDGE('',*,*,#476,.T.);
#802=DIRECTION('',(1.,0.,0.));
#803=VECTOR('',#802,1.);
#804=CARTESIAN_POINT('',(5.32705418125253,10.2,10.75));
#805=LINE('',#804,#803);
#806=EDGE_CURVE('E433',#467,#424,#805,.T.);
#807=ORIENTED_EDGE('',*,*,#806,.T.);
#808=ORIENTED_EDGE('',*,*,#425,.F.);
#809=DIRECTION('',(1.,0.,0.));
#810=VECTOR('',#809,1.);
#811=CARTESIAN_POINT('',(-5.32705418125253,14.,10.75));
#812=LINE('',#811,#810);
#813=EDGE_CURVE('E547',#475,#422,#812,.T.);
#814=ORIENTED_EDGE('',*,*,#813,.F.);
#815=EDGE_LOOP('',(#801,#807,#808,#814));
#816=FACE_BOUND('',#815,.T.);
#817=ADVANCED_FACE('F651',(#816),#800,.F.);
#818=CARTESIAN_POINT('',(0.,14.,0.));
#819=DIRECTION('',(0.,-1.,0.));
#820=DIRECTION('',(0.,0.,-1.));
#821=AXIS2_PLACEMENT_3D('',#818,#819,#820);
#822=PLANE('',#821);
#823=ORIENTED_EDGE('',*,*,#483,.T.);
#824=ORIENTED_EDGE('',*,*,#813,.T.);
#825=EDGE_LOOP('',(#823,#824));
#826=FACE_BOUND('',#825,.T.);
#827=ADVANCED_FACE('F653',(#826),#822,.T.);
#828=CARTESIAN_POINT('',(3.46410161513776,13.,0.));
#829=DIRECTION('',(-0.865497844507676,0.034899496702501,0.499695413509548));
#830=DIRECTION('',(0.5,0.,0.866025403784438));
#831=AXIS2_PLACEMENT_3D('',#828,#829,#830);
#832=PLANE('',#831);
#833=ORIENTED_EDGE('',*,*,#358,.T.);
#834=DIRECTION('',(0.0201451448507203,0.999188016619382,-0.0348924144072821));
#835=VECTOR('',#834,1.);
#836=CARTESIAN_POINT('',(1.73064498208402,12.9302718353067,-2.99756503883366));
#837=LINE('',#836,#835);
#838=CARTESIAN_POINT('',(1.73205080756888,13.,-3.));
#839=VERTEX_POINT('',#838);
#840=EDGE_CURVE('E509',#839,#357,#837,.T.);
#841=ORIENTED_EDGE('',*,*,#840,.F.);
#842=DIRECTION('',(-0.5,0.,-0.866025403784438));
#843=VECTOR('',#842,1.);
#844=CARTESIAN_POINT('',(3.46410161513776,13.,0.));
#845=LINE('',#844,#843);
#846=CARTESIAN_POINT('',(3.46410161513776,13.,0.));
#847=VERTEX_POINT('',#846);
#848=EDGE_CURVE('E429',#847,#839,#845,.T.);
#849=ORIENTED_EDGE('',*,*,#848,.F.);
#850=DIRECTION('',(0.0402902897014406,0.999188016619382,0.));
#851=VECTOR('',#850,1.);
#852=CARTESIAN_POINT('',(3.46128996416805,12.9302718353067,0.));
#853=LINE('',#852,#851);
#854=EDGE_CURVE('E506',#847,#355,#853,.T.);
#855=ORIENTED_EDGE('',*,*,#854,.T.);
#856=EDGE_LOOP('',(#833,#841,#849,#855));
#857=FACE_BOUND('',#856,.T.);
#858=ADVANCED_FACE('F655',(#857),#832,.T.);
#859=CARTESIAN_POINT('',(1.73205080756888,13.,3.));
#860=DIRECTION('',(-0.865497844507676,0.034899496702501,-0.499695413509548));
#861=DIRECTION('',(-0.5,0.,0.866025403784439));
#862=AXIS2_PLACEMENT_3D('',#859,#860,#861);
#863=PLANE('',#862);
#864=ORIENTED_EDGE('',*,*,#366,.T.);
#865=ORIENTED_EDGE('',*,*,#854,.F.);
#866=DIRECTION('',(0.5,0.,-0.866025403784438));
#867=VECTOR('',#866,1.);
#868=CARTESIAN_POINT('',(1.73205080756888,13.,3.));
#869=LINE('',#868,#867);
#870=CARTESIAN_POINT('',(1.73205080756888,13.,3.));
#871=VERTEX_POINT('',#870);
#872=EDGE_CURVE('E512',#871,#847,#869,.T.);
#873=ORIENTED_EDGE('',*,*,#872,.F.);
#874=DIRECTION('',(0.0201451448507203,0.999188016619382,0.0348924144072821));
#875=VECTOR('',#874,1.);
#876=CARTESIAN_POINT('',(1.73064498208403,12.9302718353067,2.99756503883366));
#877=LINE('',#876,#875);
#878=EDGE_CURVE('E395',#871,#365,#877,.T.);
#879=ORIENTED_EDGE('',*,*,#878,.T.);
#880=EDGE_LOOP('',(#864,#865,#873,#879));
#881=FACE_BOUND('',#880,.T.);
#882=ADVANCED_FACE('F661',(#881),#863,.T.);
#883=CARTESIAN_POINT('',(-1.73205080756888,13.,3.));
#884=DIRECTION('',(0.,0.034899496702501,-0.999390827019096));
#885=DIRECTION('',(0.,0.999390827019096,0.034899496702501));
#886=AXIS2_PLACEMENT_3D('',#883,#884,#885);
#887=PLANE('',#886);
#888=ORIENTED_EDGE('',*,*,#374,.T.);
#889=ORIENTED_EDGE('',*,*,#878,.F.);
#890=DIRECTION('',(1.,0.,0.));
#891=VECTOR('',#890,1.);
#892=CARTESIAN_POINT('',(-1.73205080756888,13.,3.));
#893=LINE('',#892,#891);
#894=CARTESIAN_POINT('',(-1.73205080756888,13.,3.));
#895=VERTEX_POINT('',#894);
#896=EDGE_CURVE('E409',#895,#871,#893,.T.);
#897=ORIENTED_EDGE('',*,*,#896,.F.);
#898=DIRECTION('',(-0.0201451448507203,0.999188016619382,0.0348924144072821));
#899=VECTOR('',#898,1.);
#900=CARTESIAN_POINT('',(-1.73064498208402,12.9302718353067,2.99756503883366));
#901=LINE('',#900,#899);
#902=EDGE_CURVE('E401',#895,#373,#901,.T.);
#903=ORIENTED_EDGE('',*,*,#902,.T.);
#904=EDGE_LOOP('',(#888,#889,#897,#903));
#905=FACE_BOUND('',#904,.T.);
#906=ADVANCED_FACE('F403',(#905),#887,.T.);
#907=CARTESIAN_POINT('',(-3.46410161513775,13.,0.));
#908=DIRECTION('',(0.865497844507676,0.034899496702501,-0.499695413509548));
#909=DIRECTION('',(-0.5,0.,-0.866025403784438));
#910=AXIS2_PLACEMENT_3D('',#907,#908,#909);
#911=PLANE('',#910);
#912=ORIENTED_EDGE('',*,*,#382,.T.);
#913=ORIENTED_EDGE('',*,*,#902,.F.);
#914=DIRECTION('',(0.5,0.,0.866025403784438));
#915=VECTOR('',#914,1.);
#916=CARTESIAN_POINT('',(-3.46410161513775,13.,0.));
#917=LINE('',#916,#915);
#918=CARTESIAN_POINT('',(-3.46410161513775,13.,0.));
#919=VERTEX_POINT('',#918);
#920=EDGE_CURVE('E539',#919,#895,#917,.T.);
#921=ORIENTED_EDGE('',*,*,#920,.F.);
#922=DIRECTION('',(-0.0402902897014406,0.999188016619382,0.));
#923=VECTOR('',#922,1.);
#924=CARTESIAN_POINT('',(-3.46128996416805,12.9302718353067,0.));
#925=LINE('',#924,#923);
#926=EDGE_CURVE('E413',#919,#381,#925,.T.);
#927=ORIENTED_EDGE('',*,*,#926,.T.);
#928=EDGE_LOOP('',(#912,#913,#921,#927));
#929=FACE_BOUND('',#928,.T.);
#930=ADVANCED_FACE('F417',(#929),#911,.T.);
#931=CARTESIAN_POINT('',(-1.73205080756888,13.,-3.));
#932=DIRECTION('',(0.865497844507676,0.034899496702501,0.499695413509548));
#933=DIRECTION('',(0.5,0.,-0.866025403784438));
#934=AXIS2_PLACEMENT_3D('',#931,#932,#933);
#935=PLANE('',#934);
#936=ORIENTED_EDGE('',*,*,#390,.T.);
#937=ORIENTED_EDGE('',*,*,#926,.F.);
#938=DIRECTION('',(-0.5,0.,0.866025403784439));
#939=VECTOR('',#938,1.);
#940=CARTESIAN_POINT('',(-1.73205080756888,13.,-3.));
#941=LINE('',#940,#939);
#942=CARTESIAN_POINT('',(-1.73205080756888,13.,-3.));
#943=VERTEX_POINT('',#942);
#944=EDGE_CURVE('E536',#943,#919,#941,.T.);
#945=ORIENTED_EDGE('',*,*,#944,.F.);
#946=DIRECTION('',(-0.0201451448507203,0.999188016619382,-0.0348924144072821));
#947=VECTOR('',#946,1.);
#948=CARTESIAN_POINT('',(-1.73064498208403,12.9302718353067,-2.99756503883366));
#949=LINE('',#948,#947);
#950=EDGE_CURVE('E504',#943,#389,#949,.T.);
#951=ORIENTED_EDGE('',*,*,#950,.T.);
#952=EDGE_LOOP('',(#936,#937,#945,#951));
#953=FACE_BOUND('',#952,.T.);
#954=ADVANCED_FACE('F800',(#953),#935,.T.);
#955=CARTESIAN_POINT('',(1.73205080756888,13.,-3.));
#956=DIRECTION('',(0.,0.034899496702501,0.999390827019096));
#957=DIRECTION('',(0.,-0.999390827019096,0.034899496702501));
#958=AXIS2_PLACEMENT_3D('',#955,#956,#957);
#959=PLANE('',#958);
#960=ORIENTED_EDGE('',*,*,#396,.T.);
#961=ORIENTED_EDGE('',*,*,#950,.F.);
#962=DIRECTION('',(-1.,0.,0.));
#963=VECTOR('',#962,1.);
#964=CARTESIAN_POINT('',(1.73205080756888,13.,-3.));
#965=LINE('',#964,#963);
#966=EDGE_CURVE('E533',#839,#943,#965,.T.);
#967=ORIENTED_EDGE('',*,*,#966,.F.);
#968=ORIENTED_EDGE('',*,*,#840,.T.);
#969=EDGE_LOOP('',(#960,#961,#967,#968));
#970=FACE_BOUND('',#969,.T.);
#971=ADVANCED_FACE('F809',(#970),#959,.T.);
#972=CARTESIAN_POINT('',(0.,13.,0.));
#973=DIRECTION('',(0.,1.,0.));
#974=DIRECTION('',(0.,0.,1.));
#975=AXIS2_PLACEMENT_3D('',#972,#973,#974);
#976=PLANE('',#975);
#977=CARTESIAN_POINT('',(0.,13.,0.));
#978=DIRECTION('',(0.,1.,0.));
#979=DIRECTION('',(0.,0.,1.));
#980=AXIS2_PLACEMENT_3D('',#977,#978,#979);
#981=CIRCLE('',#980,2.25);
#982=CARTESIAN_POINT('',(0.,13.,2.25));
#983=VERTEX_POINT('',#982);
#984=EDGE_CURVE('E456',#983,#983,#981,.T.);
#985=ORIENTED_EDGE('',*,*,#984,.F.);
#986=EDGE_LOOP('',(#985));
#987=FACE_BOUND('',#986,.T.);
#988=ORIENTED_EDGE('',*,*,#848,.T.);
#989=ORIENTED_EDGE('',*,*,#966,.T.);
#990=ORIENTED_EDGE('',*,*,#944,.T.);
#991=ORIENTED_EDGE('',*,*,#920,.T.);
#992=ORIENTED_EDGE('',*,*,#896,.T.);
#993=ORIENTED_EDGE('',*,*,#872,.T.);
#994=EDGE_LOOP('',(#988,#989,#990,#991,#992,#993));
#995=FACE_BOUND('',#994,.T.);
#996=ADVANCED_FACE('F820',(#987,#995),#976,.T.);
#997=CARTESIAN_POINT('',(9.2,9.15,0.));
#998=DIRECTION('',(0.,-1.,0.));
#999=DIRECTION('',(1.,0.,0.));
#1000=AXIS2_PLACEMENT_3D('',#997,#998,#999);
#1001=SPHERICAL_SURFACE('',#1000,1.25);
#1002=ORIENTED_EDGE('',*,*,#616,.T.);
#1003=EDGE_LOOP('',(#1002));
#1004=FACE_BOUND('',#1003,.T.);
#1005=ADVANCED_FACE('F829',(#1004),#1001,.F.);
#1006=CARTESIAN_POINT('',(6.50538238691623,9.15,6.50538238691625));
#1007=DIRECTION('',(0.,-1.,0.));
#1008=DIRECTION('',(0.707106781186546,0.,0.707106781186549));
#1009=AXIS2_PLACEMENT_3D('',#1006,#1007,#1008);
#1010=SPHERICAL_SURFACE('',#1009,1.25);
#1011=ORIENTED_EDGE('',*,*,#605,.T.);
#1012=EDGE_LOOP('',(#1011));
#1013=FACE_BOUND('',#1012,.T.);
#1014=ADVANCED_FACE('F917',(#1013),#1010,.F.);
#1015=CARTESIAN_POINT('',(0.,9.15,9.2));
#1016=DIRECTION('',(0.,-1.,0.));
#1017=DIRECTION('',(0.,0.,1.));
#1018=AXIS2_PLACEMENT_3D('',#1015,#1016,#1017);
#1019=SPHERICAL_SURFACE('',#1018,1.25);
#1020=ORIENTED_EDGE('',*,*,#594,.T.);
#1021=EDGE_LOOP('',(#1020));
#1022=FACE_BOUND('',#1021,.T.);
#1023=ADVANCED_FACE('F907',(#1022),#1019,.F.);
#1024=CARTESIAN_POINT('',(-6.50538238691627,9.15,6.5053823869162));
#1025=DIRECTION('',(0.,-1.,0.));
#1026=DIRECTION('',(-0.707106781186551,0.,0.707106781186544));
#1027=AXIS2_PLACEMENT_3D('',#1024,#1025,#1026);
#1028=SPHERICAL_SURFACE('',#1027,1.25);
#1029=ORIENTED_EDGE('',*,*,#583,.T.);
#1030=EDGE_LOOP('',(#1029));
#1031=FACE_BOUND('',#1030,.T.);
#1032=ADVANCED_FACE('F897',(#1031),#1028,.F.);
#1033=CARTESIAN_POINT('',(-9.2,9.15,0.));
#1034=DIRECTION('',(0.,-1.,0.));
#1035=DIRECTION('',(-1.,0.,0.));
#1036=AXIS2_PLACEMENT_3D('',#1033,#1034,#1035);
#1037=SPHERICAL_SURFACE('',#1036,1.25);
#1038=ORIENTED_EDGE('',*,*,#572,.T.);
#1039=EDGE_LOOP('',(#1038));
#1040=FACE_BOUND('',#1039,.T.);
#1041=ADVANCED_FACE('F887',(#1040),#1037,.F.);
#1042=CARTESIAN_POINT('',(-6.50538238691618,9.15,-6.50538238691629));
#1043=DIRECTION('',(0.,-1.,0.));
#1044=DIRECTION('',(-0.707106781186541,0.,-0.707106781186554));
#1045=AXIS2_PLACEMENT_3D('',#1042,#1043,#1044);
#1046=SPHERICAL_SURFACE('',#1045,1.25);
#1047=ORIENTED_EDGE('',*,*,#561,.T.);
#1048=EDGE_LOOP('',(#1047));
#1049=FACE_BOUND('',#1048,.T.);
#1050=ADVANCED_FACE('F877',(#1049),#1046,.F.);
#1051=CARTESIAN_POINT('',(0.,9.15,-9.2));
#1052=DIRECTION('',(0.,-1.,0.));
#1053=DIRECTION('',(0.,0.,-1.));
#1054=AXIS2_PLACEMENT_3D('',#1051,#1052,#1053);
#1055=SPHERICAL_SURFACE('',#1054,1.25);
#1056=ORIENTED_EDGE('',*,*,#550,.T.);
#1057=EDGE_LOOP('',(#1056));
#1058=FACE_BOUND('',#1057,.T.);
#1059=ADVANCED_FACE('F867',(#1058),#1055,.F.);
#1060=CARTESIAN_POINT('',(6.50538238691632,9.15,-6.50538238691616));
#1061=DIRECTION('',(0.,-1.,0.));
#1062=DIRECTION('',(0.707106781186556,0.,-0.707106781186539));
#1063=AXIS2_PLACEMENT_3D('',#1060,#1061,#1062);
#1064=SPHERICAL_SURFACE('',#1063,1.25);
#1065=ORIENTED_EDGE('',*,*,#539,.T.);
#1066=EDGE_LOOP('',(#1065));
#1067=FACE_BOUND('',#1066,.T.);
#1068=ADVANCED_FACE('F731',(#1067),#1064,.F.);
#1069=CARTESIAN_POINT('',(-5.32705418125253,10.2,10.75));
#1070=DIRECTION('',(0.,-0.707106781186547,0.707106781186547));
#1071=DIRECTION('',(-1.,0.,0.));
#1072=AXIS2_PLACEMENT_3D('',#1069,#1070,#1071);
#1073=PLANE('',#1072);
#1074=CARTESIAN_POINT('',(-5.28001006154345,10.,10.55));
#1075=CARTESIAN_POINT('',(-5.28788458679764,10.0333293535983,10.5833293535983));
#1076=CARTESIAN_POINT('',(-5.29574219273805,10.0666606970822,10.6166606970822));
#1077=CARTESIAN_POINT('',(-5.31142356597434,10.1333273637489,10.6833273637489));
#1078=CARTESIAN_POINT('',(-5.31924733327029,10.1666626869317,10.7166626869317));
#1079=CARTESIAN_POINT('',(-5.32705418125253,10.2,10.75));
#1080=B_SPLINE_CURVE_WITH_KNOTS('',3,(#1074,#1075,#1076,#1077,#1078,#1079),.UNSPECIFIED.,.F.,
.F.,(4,2,4),(0.,0.143364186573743,0.286728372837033),.UNSPECIFIED.);
#1081=EDGE_CURVE('E497',#502,#467,#1080,.T.);
#1082=ORIENTED_EDGE('',*,*,#1081,.F.);
#1083=ORIENTED_EDGE('',*,*,#528,.F.);
#1084=CARTESIAN_POINT('',(5.28001006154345,10.,10.55));
#1085=CARTESIAN_POINT('',(5.28788458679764,10.0333293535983,10.5833293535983));
#1086=CARTESIAN_POINT('',(5.29574219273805,10.0666606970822,10.6166606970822));
#1087=CARTESIAN_POINT('',(5.31142356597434,10.1333273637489,10.6833273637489));
#1088=CARTESIAN_POINT('',(5.31924733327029,10.1666626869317,10.7166626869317));
#1089=CARTESIAN_POINT('',(5.32705418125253,10.2,10.75));
#1090=B_SPLINE_CURVE_WITH_KNOTS('',3,(#1084,#1085,#1086,#1087,#1088,#1089),.UNSPECIFIED.,.F.,
.F.,(4,2,4),(0.,0.143364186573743,0.286728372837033),.UNSPECIFIED.);
#1091=EDGE_CURVE('E490',#424,#521,#1090,.F.);
#1092=ORIENTED_EDGE('',*,*,#1091,.F.);
#1093=ORIENTED_EDGE('',*,*,#806,.F.);
#1094=EDGE_LOOP('',(#1082,#1083,#1092,#1093));
#1095=FACE_BOUND('',#1094,.T.);
#1096=ADVANCED_FACE('F484',(#1095),#1073,.T.);
#1097=CARTESIAN_POINT('',(0.,10.,0.));
#1098=DIRECTION('',(0.,1.,0.));
#1099=DIRECTION('',(0.,0.,1.));
#1100=AXIS2_PLACEMENT_3D('',#1097,#1098,#1099);
#1101=CONICAL_SURFACE('',#1100,11.7975,0.785398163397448);
#1102=ORIENTED_EDGE('',*,*,#1091,.T.);
#1103=ORIENTED_EDGE('',*,*,#522,.F.);
#1104=CARTESIAN_POINT('',(5.28001006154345,10.,-10.55));
#1105=CARTESIAN_POINT('',(5.28788458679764,10.0333293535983,-10.5833293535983));
#1106=CARTESIAN_POINT('',(5.29574219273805,10.0666606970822,-10.6166606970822));
#1107=CARTESIAN_POINT('',(5.31142356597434,10.1333273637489,-10.6833273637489));
#1108=CARTESIAN_POINT('',(5.31924733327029,10.1666626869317,-10.7166626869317));
#1109=CARTESIAN_POINT('',(5.32705418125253,10.2,-10.75));
#1110=B_SPLINE_CURVE_WITH_KNOTS('',3,(#1104,#1105,#1106,#1107,#1108,#1109),.UNSPECIFIED.,.F.,
.F.,(4,2,4),(0.,0.143364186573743,0.286728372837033),.UNSPECIFIED.);
#1111=EDGE_CURVE('E455',#433,#512,#1110,.F.);
#1112=ORIENTED_EDGE('',*,*,#1111,.F.);
#1113=ORIENTED_EDGE('',*,*,#434,.F.);
#1114=EDGE_LOOP('',(#1102,#1103,#1112,#1113));
#1115=FACE_BOUND('',#1114,.T.);
#1116=ADVANCED_FACE('F476',(#1115),#1101,.T.);
#1117=CARTESIAN_POINT('',(0.,10.,0.));
#1118=DIRECTION('',(0.,1.,0.));
#1119=DIRECTION('',(0.,0.,1.));
#1120=AXIS2_PLACEMENT_3D('',#1117,#1118,#1119);
#1121=CONICAL_SURFACE('',#1120,11.7975,0.785398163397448);
#1122=ORIENTED_EDGE('',*,*,#1081,.T.);
#1123=ORIENTED_EDGE('',*,*,#468,.F.);
#1124=CARTESIAN_POINT('',(-5.32705418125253,10.2,-10.75));
#1125=CARTESIAN_POINT('',(-5.31924733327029,10.1666626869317,-10.7166626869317));
#1126=CARTESIAN_POINT('',(-5.31142356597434,10.1333273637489,-10.6833273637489));
#1127=CARTESIAN_POINT('',(-5.29574219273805,10.0666606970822,-10.6166606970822));
#1128=CARTESIAN_POINT('',(-5.28788458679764,10.0333293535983,-10.5833293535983));
#1129=CARTESIAN_POINT('',(-5.28001006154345,10.,-10.55));
#1130=B_SPLINE_CURVE_WITH_KNOTS('',3,(#1124,#1125,#1126,#1127,#1128,#1129),.UNSPECIFIED.,.F.,
.F.,(4,2,4),(0.,0.143364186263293,0.286728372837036),.UNSPECIFIED.);
#1131=EDGE_CURVE('E446',#504,#458,#1130,.F.);
#1132=ORIENTED_EDGE('',*,*,#1131,.F.);
#1133=ORIENTED_EDGE('',*,*,#505,.F.);
#1134=EDGE_LOOP('',(#1122,#1123,#1132,#1133));
#1135=FACE_BOUND('',#1134,.T.);
#1136=ADVANCED_FACE('F464',(#1135),#1121,.T.);
#1137=CARTESIAN_POINT('',(-5.32705418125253,10.2,-10.75));
#1138=DIRECTION('',(0.,-0.707106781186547,-0.707106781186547));
#1139=DIRECTION('',(1.,0.,0.));
#1140=AXIS2_PLACEMENT_3D('',#1137,#1138,#1139);
#1141=PLANE('',#1140);
#1142=ORIENTED_EDGE('',*,*,#1111,.T.);
#1143=ORIENTED_EDGE('',*,*,#513,.F.);
#1144=ORIENTED_EDGE('',*,*,#1131,.T.);
#1145=ORIENTED_EDGE('',*,*,#774,.F.);
#1146=EDGE_LOOP('',(#1142,#1143,#1144,#1145));
#1147=FACE_BOUND('',#1146,.T.);
#1148=ADVANCED_FACE('F468',(#1147),#1141,.T.);
#1149=CARTESIAN_POINT('',(0.,0.,0.));
#1150=DIRECTION('',(0.,1.,0.));
#1151=DIRECTION('',(0.,0.,1.));
#1152=AXIS2_PLACEMENT_3D('',#1149,#1150,#1151);
#1153=CYLINDRICAL_SURFACE('',#1152,2.25);
#1154=CARTESIAN_POINT('',(0.,0.750000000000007,0.));
#1155=DIRECTION('',(0.,-1.,0.));
#1156=DIRECTION('',(0.,0.,-1.));
#1157=AXIS2_PLACEMENT_3D('',#1154,#1155,#1156);
#1158=CIRCLE('',#1157,2.25);
#1159=CARTESIAN_POINT('',(0.,0.750000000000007,-2.25));
#1160=VERTEX_POINT('',#1159);
#1161=EDGE_CURVE('E52',#1160,#1160,#1158,.T.);
#1162=ORIENTED_EDGE('',*,*,#1161,.T.);
#1163=EDGE_LOOP('',(#1162));
#1164=FACE_BOUND('',#1163,.T.);
#1165=ORIENTED_EDGE('',*,*,#984,.T.);
#1166=EDGE_LOOP('',(#1165));
#1167=FACE_BOUND('',#1166,.T.);
#1168=ADVANCED_FACE('F474',(#1164,#1167),#1153,.F.);
#1169=CARTESIAN_POINT('',(0.,0.,0.));
#1170=DIRECTION('',(0.,-1.,0.));
#1171=DIRECTION('',(0.,0.,-1.));
#1172=AXIS2_PLACEMENT_3D('',#1169,#1170,#1171);
#1173=CONICAL_SURFACE('',#1172,3.00000000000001,0.78539816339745);
#1174=ORIENTED_EDGE('',*,*,#1161,.F.);
#1175=EDGE_LOOP('',(#1174));
#1176=FACE_BOUND('',#1175,.T.);
#1177=ORIENTED_EDGE('',*,*,#329,.F.);
#1178=EDGE_LOOP('',(#1177));
#1179=FACE_BOUND('',#1178,.T.);
#1180=ADVANCED_FACE('F353',(#1176,#1179),#1173,.F.);
#1181=CLOSED_SHELL('',(#344,#411,#490,#631,#651,#671,#691,#711,#731,#751,#763,#785,#795,#817,
#827,#858,#882,#906,#930,#954,#971,#996,#1005,#1014,#1023,#1032,#1041,#1050,#1059,#1068,#1096,
#1116,#1136,#1148,#1168,#1180));
#1182=MANIFOLD_SOLID_BREP('B6',#1181);
#1183=ADVANCED_BREP_SHAPE_REPRESENTATION('',(#18,#316,#1182),#14);
#1184=SHAPE_DEFINITION_REPRESENTATION(#9,#1183);
ENDSEC;
END-ISO-10303-21;
